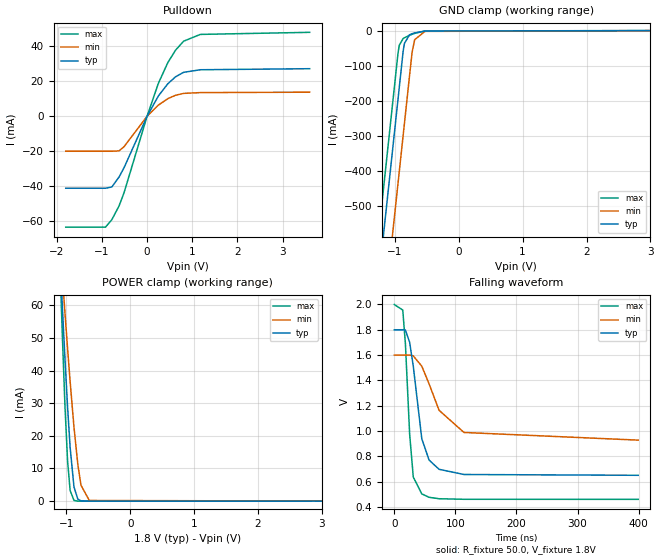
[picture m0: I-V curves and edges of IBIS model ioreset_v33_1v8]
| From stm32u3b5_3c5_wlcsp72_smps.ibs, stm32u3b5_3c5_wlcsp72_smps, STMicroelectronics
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[Model]   ioreset_v33_1v8
Model_type I/O_open_drain
Polarity   Inverting
Enable   Active-Low
| CAP_THRESHOLD on pad IOFT is "UDTCAPC" :
| Rising=30.0% of vddiom   Falling=70.0% of vddiom
| C_comp min and max val. don't necessarily correlate with the min and max pvt
| but are the smallest and greatest pad capacitance found.
| var   typ   min   max
C_comp   3.05599pF  3.03121pF  3.12525pF
|C_comp_pulldown   3.05599pF  3.03121pF  3.12525pF
Vinl = 800.0mV
Vinh = 1.0V
Vmeas = 900.0mV   | Reference voltage for timing measurements
Cref  = 50.0pF   | Timing specification test load capacitance value
Rref  = 1.0MOhm   | Timing specification test load resistance value
Vref  = 990.0mV   | Timing specification test load voltage
[Model Spec]
| TIME_THRESHOLD on pin ZIV33M is "CMOS" :
| Rising=50.0% of vddiom   Falling=50.0% of vddiom
Vinl 692.50000mV 616.50000mV 775.50000mV
Vinh 1.07650V 950.50000mV 1.18050V
| variable   typ   min   max
[Temperature Range] 25.0 130.0 -40.0
| variable   typ   min   max
[Voltage Range] 1.8V 1.6V 2.0V
| variable   typ   min   max
[POWER Clamp Reference] 1.8V 1.6V 2.0V
| variable   typ   min   max
[GND Clamp Reference] 0V 0V 0V
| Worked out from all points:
|   slope of the pulldown table from 0 to 0.27 V, typ, clamps not added: 21.9 ohm
|   GND clamp passes 1 mA (typ) near -0.50 V on its own axis
|   POWER clamp passes 1 mA (typ) near -0.83 V on its own axis
|   falling waveform, R_fixture 50.0, V_fixture 1.8V: 20-80 % time 18.6ns typ, 39.5ns min, 10.6ns max; typ from 1.8 V to 0.65 V
[POWER Clamp]
-1.8V     399.1mA    292.1mA    557.7mA
-1.09V    71.2mA     76.8mA     67.14mA
-1.08V    67.05mA    73.98mA    61.2mA
-1.06V    58.89mA    68.38mA    49.67mA
-1.02V    43.22mA    57.4mA     28.67mA
-980mV    28.81mA    46.77mA    12.28mA
-940mV    16.45mA    36.61mA    3.257mA
-880mV    4.35mA     22.67mA    225.4uA
-820mV    610.4uA    11.29mA    13uA
-770mV    97.5uA     4.87mA     1.193uA
-640mV    753.7nA    196.1uA    2.435nA
3.6V      0A         0A         0A
[GND Clamp]
-1.8V     -1.64A     -1.88A     -1.509A
-1.24V    -688.2mA   -927.9mA   -557mA
-1.05V    -365.2mA   -604.9mA   -234mA
-950mV    -195.2mA   -434.9mA   -63.99mA
-930mV    -161.2mA   -400.9mA   -41.58mA
-870mV    -59.19mA   -298.9mA   -22.93mA
-850mV    -36.72mA   -264.9mA   -20.63mA
-770mV    -12.2mA    -128.9mA   -13.72mA
-730mV    -9.131mA   -62.09mA   -10.8mA
-690mV    -6.963mA   -26.32mA   -8.19mA
-530mV    -1.56mA    -2.409mA   -1.403mA
3.6V      565.7pA    21.53nA    420.7pA
| variable   typ   min   max
[Pullup Reference] 1.8V 1.6V 2.0V
| variable   typ   min   max
[Pulldown Reference] 0V 0V 0V
[Pulldown]
-1.8V     -41.16mA   -19.96mA   -63.43mA
-920mV    -41.16mA   -19.96mA   -63.43mA
-780mV    -40.43mA   -19.96mA   -59.18mA
-620mV    -34.74mA   -19.77mA   -51.3mA
-510mV    -29.46mA   -17.38mA   -43.8mA
0V        0A         0A         0A
250mV     11.64mA    6.428mA    18.87mA
460mV     18.67mA    10.12mA    30.76mA
630mV     22.61mA    12.05mA    37.86mA
810mV     25.21mA    13.14mA    43.03mA
1.18V     26.67mA    13.59mA    46.9mA
3.6V      27.27mA    13.83mA    48.09mA
[Ramp]
dV/dt_r 690.56433mV/303.78135ps 403.00475mV/600.01926ps 920.43601mV/212.38204ps
dV/dt_f 689.75457mV/18.18087ns 402.99331mV/39.455ns 923.68055mV/9.41935ns
R_load = 50.0
| Removed startup time: 0s 0s 0s  .
| Removed end time: 99.99us.
|[Rising Waveform]
|R_fixture   = 50.0
|V_fixture   = 1.8V
|V_fixture_min = 1.6V
|V_fixture_max = 2.0V
|  0s  650.40903mV  928.33026mV  460.53240mV
|  10.0ns  650.40903mV  928.33015mV  460.53239mV
|  2.04us  650.40903mV  928.33015mV  460.53239mV
|  4.08us  650.40903mV  928.33015mV  460.53239mV
|  6.12us  650.40903mV  928.33015mV  460.53239mV
|  8.16us  650.40903mV  928.33015mV  460.53239mV
|  10.2us  650.40903mV  928.33015mV  460.53239mV
|  12.24us  650.40903mV  928.33015mV  460.53239mV
|  14.29us  650.40903mV  928.33015mV  460.53239mV
|  16.33us  650.40903mV  928.33015mV  460.53239mV
|  18.37us  650.40903mV  928.33015mV  460.53239mV
|  20.41us  650.40903mV  928.33015mV  460.53239mV
|  22.45us  650.40903mV  928.33015mV  460.53239mV
|  24.49us  650.40903mV  928.33015mV  460.53239mV
|  26.53us  650.40903mV  928.33015mV  460.53239mV
|  28.57us  650.40903mV  928.33015mV  460.53239mV
|  30.61us  650.40903mV  928.33015mV  460.53239mV
|  32.65us  650.40903mV  928.33015mV  460.53239mV
|  33.13us  650.40903mV  928.33015mV  460.53239mV
|  33.17us  650.40903mV  928.33015mV  460.53239mV
|  33.18us  650.40903mV  928.33015mV  460.53239mV
|  33.21us  650.40903mV  928.33015mV  460.53239mV
|  33.24us  650.40903mV  928.33015mV  460.53239mV
|  33.37us  650.40903mV  928.33015mV  460.53239mV
|  33.38us  650.40903mV  928.33015mV  460.53239mV
|  33.43us  650.40903mV  928.33015mV  460.53239mV
|  34.69us  650.40903mV  928.33015mV  460.53239mV
|  34.91us  650.40903mV  928.33015mV  460.53239mV
|  34.92us  650.40903mV  928.33015mV  460.53248mV
|  34.93us  650.40903mV  928.33015mV  1.99983V
|  34.94us  650.40903mV  928.33015mV  1.99995V
|  34.95us  650.40903mV  928.33015mV  1.99997V
|  34.96us  650.40903mV  928.33015mV  1.99998V
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[Falling Waveform]
R_fixture   = 50.0
V_fixture   = 1.8V
V_fixture_min = 1.6V
V_fixture_max = 2.0V
0s        1.8V       1.6V       2V
13.95ns   1.8V       1.6V       1.956V
18.25ns   1.798V     1.6V       1.689V
25.2ns    1.701V     1.6V       974.5mV
31.15ns   1.512V     1.594V     636.1mV
45.1ns    938.4mV    1.512V     503.2mV
57.05ns   770.3mV    1.372V     476.6mV
73.35ns   697.7mV    1.164V     465.2mV
114.1ns   656.7mV    988.8mV    460.8mV
399.3ns   650.4mV    928.3mV    460.5mV
